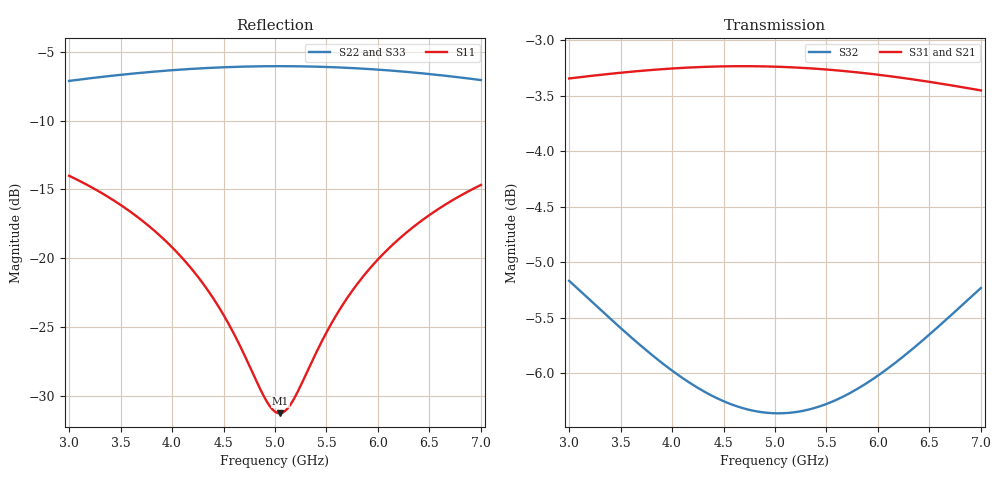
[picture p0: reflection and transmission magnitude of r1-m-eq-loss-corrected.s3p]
! yapnr Order 0 prediction r1-m-eq: predictions/run0b/r1-m-eq.s3p, loss-corrected
! substrate M-eq; coupon model OSHPARK-4L-FR408HR; correction: path [('arm', 9.2), ('line', 6.0)]
! |S21|, |S31| (and S12, S13) scaled, phases kept; 50 ohm, e^(+jwt)
# GHz S RI R 50
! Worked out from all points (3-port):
!   161 points, 3 GHz to 7 GHz, reference 50 ohm
!   strongest paths, dB at 3 GHz, 4 GHz, 5 GHz, 6 GHz, 7 GHz:
!     S31: -3.3, -3.3, -3.2, -3.3, -3.5
!     S21: -3.3, -3.3, -3.2, -3.3, -3.5
!     S32: -5.2, -6.0, -6.4, -6.0, -5.2
!   lowest |S11| = -31.3 dB at 5.05 GHz (marker M1), VSWR 1.06, Z = 47.3 - j0.00716 ohm
!   |S11| at or under -10 dB: start of sweep to end of sweep
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3  -0.1356 0.1462  0.027 -0.6797  0.027 -0.6797
   0.0271 -0.6798  -0.2167 0.3848  0.1014 -0.5423
   0.0271 -0.6798  0.1014 -0.5423  -0.2167 0.3848
3.625  -0.0828 0.1188  -0.1961 -0.6565  -0.1961 -0.6565
       -0.196 -0.6567  -0.1 0.459  -0.0276 -0.5185
       -0.196 -0.6567  -0.0276 -0.5185  -0.1 0.459
4.125  -0.0509 0.0833  -0.3635 -0.5839  -0.3635 -0.5839
       -0.3635 -0.5841  0.0171 0.4864  -0.1107 -0.4855
       -0.3635 -0.5841  -0.1107 -0.4855  0.0171 0.4864
4.475  -0.0361 0.0534  -0.4667 -0.5066  -0.4667 -0.5066
       -0.4667 -0.5068  0.1049 0.4833  -0.1601 -0.4605
       -0.4667 -0.5068  -0.1601 -0.4605  0.1049 0.4833
5  -0.0272 0.00464  -0.5891 -0.3565  -0.5891 -0.3565
   -0.5892 -0.3568  0.2324 0.4422  -0.227 -0.424
   -0.5892 -0.3568  -0.227 -0.424  0.2324 0.4422
5.05  -0.0273 -7.56e-05  -0.5983 -0.3405  -0.5983 -0.3405
      -0.5984 -0.3407  0.2438 0.4361  -0.2333 -0.4206
      -0.5984 -0.3407  -0.2333 -0.4206  0.2438 0.4361
5.175  -0.028 -0.0118  -0.6195 -0.2994  -0.6195 -0.2994
       -0.6196 -0.2996  0.2711 0.4193  -0.2488 -0.412
       -0.6196 -0.2996  -0.2488 -0.412  0.2711 0.4193
5.625  -0.0379 -0.0524  -0.6709 -0.1418  -0.6709 -0.1418
       -0.6711 -0.142  0.3559 0.343  -0.3067 -0.3801
       -0.6711 -0.142  -0.3067 -0.3801  0.3559 0.343
5.95  -0.0518 -0.0789  -0.6829 -0.0233  -0.6829 -0.0233
      -0.6831 -0.0234  0.4007 0.2764  -0.3511 -0.3535
      -0.6831 -0.0234  -0.3511 -0.3535  0.4007 0.2764
7  -0.1247 -0.1363  -0.5815 0.3365  -0.5815 0.3365
   -0.5817 0.3364  0.4423 0.0469  -0.5026 -0.2174
   -0.5817 0.3364  -0.5026 -0.2174  0.4423 0.0469
